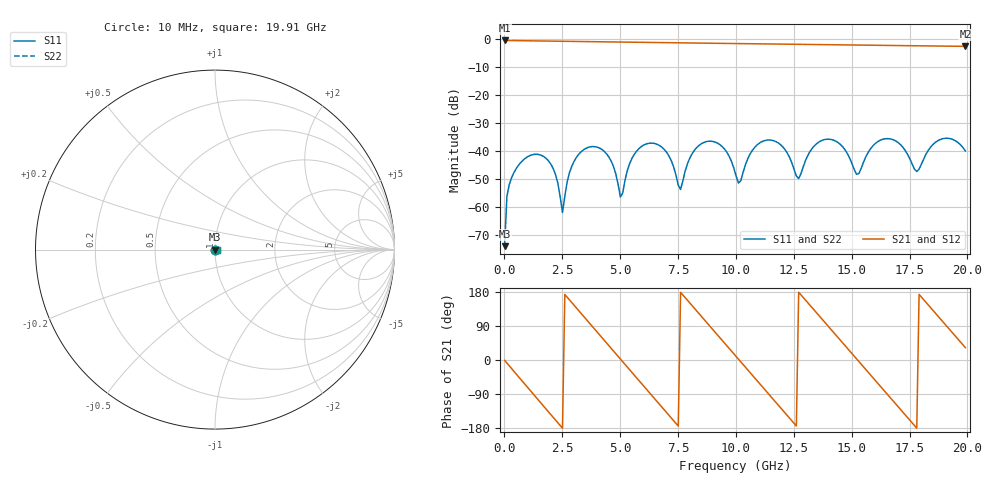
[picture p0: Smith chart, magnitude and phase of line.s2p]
# Hz S RI R 50.0
!freq ReS11 ImS11 ReS21 ImS21 ReS12 ImS12 ReS22 ImS22
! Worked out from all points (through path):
!   200 points, 10 MHz to 19.91 GHz, reference 50 ohm
!   highest |S21| = -0.36 dB at 10 MHz (marker M1); lowest = -2.5 dB at 19.91 GHz (marker M2)
!   group delay of S21, straight-line fit = 196 ps
!   lowest |S11| = -74.1 dB at 10 MHz (marker M3), VSWR 1.00, Z = 50 - j0.0193 ohm
!   |S11| at or under -10 dB: start of sweep to end of sweep
!   |S22| runs from -74.1 to -35.4 dB; largest |S21 - S12| = 4.7e-16
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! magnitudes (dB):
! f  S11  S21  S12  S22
! 10 MHz  -74.1  -0.4  -0.4  -74.1
! 110 MHz  -56.2  -0.4  -0.4  -56.2
! 610 MHz  -45.1  -0.4  -0.4  -45.1
! 1.91 GHz  -43.6  -0.6  -0.6  -43.6
! 2.51 GHz  -62.0  -0.7  -0.7  -62.0
! 3.41 GHz  -39.6  -0.8  -0.8  -39.6
! 4.41 GHz  -41.0  -0.9  -0.9  -41.0
! 5.01 GHz  -56.4  -0.9  -0.9  -56.4
! 5.71 GHz  -40.0  -1.0  -1.0  -40.0
! 6.71 GHz  -38.1  -1.1  -1.1  -38.1
! 7.61 GHz  -53.8  -1.2  -1.2  -53.8
! 8.71 GHz  -36.7  -1.3  -1.3  -36.7
! 10.01 GHz  -49.0  -1.5  -1.5  -49.0
! 11.41 GHz  -36.0  -1.6  -1.6  -36.0
! 12.71 GHz  -49.9  -1.8  -1.8  -49.9
! 13.31 GHz  -38.9  -1.8  -1.8  -38.9
! 14.31 GHz  -36.5  -1.9  -1.9  -36.5
! 15.21 GHz  -48.3  -2.0  -2.0  -48.3
! 16.61 GHz  -35.6  -2.1  -2.1  -35.6
! 17.81 GHz  -47.3  -2.3  -2.3  -47.3
! 18.81 GHz  -35.9  -2.4  -2.4  -35.9
! 19.91 GHz  -40.0  -2.5  -2.5  -40.0
